VERSION 5.7 ;
  NOWIREEXTENSIONATPIN ON ;
  DIVIDERCHAR "/" ;
  BUSBITCHARS "[]" ;
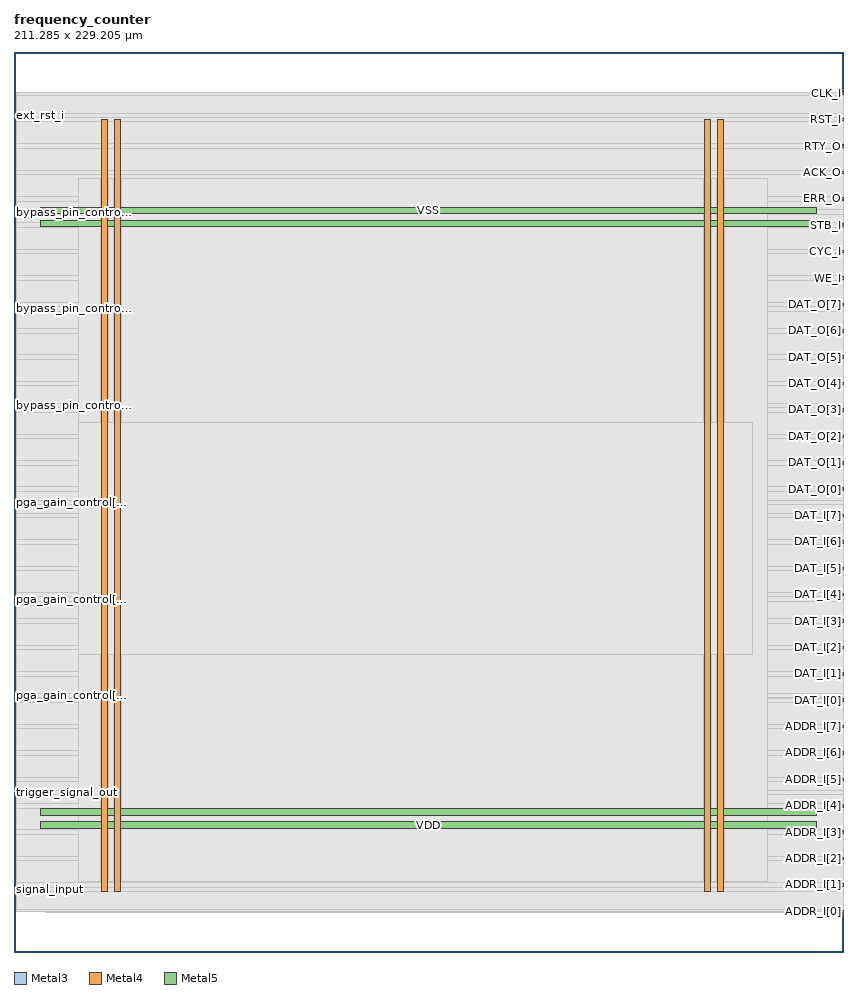
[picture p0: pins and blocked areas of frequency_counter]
MACRO frequency_counter
  CLASS BLOCK ;
  FOREIGN frequency_counter ;
  ORIGIN 0.000 0.000 ;
  SIZE 211.285 BY 229.205 ;
  PIN ACK_O
    DIRECTION OUTPUT ;
    USE SIGNAL ;
    ANTENNADIFFAREA 0.897600 ;
    PORT
      LAYER Metal3 ;
        RECT 210.725 198.240 211.285 198.800 ;
    END
  END ACK_O
  PIN ADDR_I[0]
    DIRECTION INPUT ;
    USE SIGNAL ;
    ANTENNAGATEAREA 0.396000 ;
    PORT
      LAYER Metal3 ;
        RECT 210.725 10.080 211.285 10.640 ;
    END
  END ADDR_I[0]
  PIN ADDR_I[1]
    DIRECTION INPUT ;
    USE SIGNAL ;
    ANTENNAGATEAREA 0.396000 ;
    PORT
      LAYER Metal3 ;
        RECT 210.725 16.800 211.285 17.360 ;
    END
  END ADDR_I[1]
  PIN ADDR_I[2]
    DIRECTION INPUT ;
    USE SIGNAL ;
    ANTENNAGATEAREA 0.396000 ;
    PORT
      LAYER Metal3 ;
        RECT 210.725 23.520 211.285 24.080 ;
    END
  END ADDR_I[2]
  PIN ADDR_I[3]
    DIRECTION INPUT ;
    USE SIGNAL ;
    ANTENNAGATEAREA 0.396000 ;
    PORT
      LAYER Metal3 ;
        RECT 210.725 30.240 211.285 30.800 ;
    END
  END ADDR_I[3]
  PIN ADDR_I[4]
    DIRECTION INPUT ;
    USE SIGNAL ;
    ANTENNAGATEAREA 0.396000 ;
    PORT
      LAYER Metal3 ;
        RECT 210.725 36.960 211.285 37.520 ;
    END
  END ADDR_I[4]
  PIN ADDR_I[5]
    DIRECTION INPUT ;
    USE SIGNAL ;
    ANTENNAGATEAREA 0.396000 ;
    PORT
      LAYER Metal3 ;
        RECT 210.725 43.680 211.285 44.240 ;
    END
  END ADDR_I[5]
  PIN ADDR_I[6]
    DIRECTION INPUT ;
    USE SIGNAL ;
    ANTENNAGATEAREA 0.396000 ;
    PORT
      LAYER Metal3 ;
        RECT 210.725 50.400 211.285 50.960 ;
    END
  END ADDR_I[6]
  PIN ADDR_I[7]
    DIRECTION INPUT ;
    USE SIGNAL ;
    ANTENNAGATEAREA 0.396000 ;
    PORT
      LAYER Metal3 ;
        RECT 210.725 57.120 211.285 57.680 ;
    END
  END ADDR_I[7]
  PIN CLK_I
    DIRECTION INPUT ;
    USE SIGNAL ;
    ANTENNAGATEAREA 4.738000 ;
    PORT
      LAYER Metal3 ;
        RECT 210.725 218.400 211.285 218.960 ;
    END
  END CLK_I
  PIN CYC_I
    DIRECTION INPUT ;
    USE SIGNAL ;
    ANTENNAGATEAREA 0.396000 ;
    PORT
      LAYER Metal3 ;
        RECT 210.725 178.080 211.285 178.640 ;
    END
  END CYC_I
  PIN DAT_I[0]
    DIRECTION INPUT ;
    USE SIGNAL ;
    ANTENNAGATEAREA 0.396000 ;
    PORT
      LAYER Metal3 ;
        RECT 210.725 63.840 211.285 64.400 ;
    END
  END DAT_I[0]
  PIN DAT_I[1]
    DIRECTION INPUT ;
    USE SIGNAL ;
    ANTENNAGATEAREA 0.396000 ;
    PORT
      LAYER Metal3 ;
        RECT 210.725 70.560 211.285 71.120 ;
    END
  END DAT_I[1]
  PIN DAT_I[2]
    DIRECTION INPUT ;
    USE SIGNAL ;
    ANTENNAGATEAREA 0.396000 ;
    PORT
      LAYER Metal3 ;
        RECT 210.725 77.280 211.285 77.840 ;
    END
  END DAT_I[2]
  PIN DAT_I[3]
    DIRECTION INPUT ;
    USE SIGNAL ;
    ANTENNAGATEAREA 0.396000 ;
    PORT
      LAYER Metal3 ;
        RECT 210.725 84.000 211.285 84.560 ;
    END
  END DAT_I[3]
  PIN DAT_I[4]
    DIRECTION INPUT ;
    USE SIGNAL ;
    ANTENNAGATEAREA 0.396000 ;
    PORT
      LAYER Metal3 ;
        RECT 210.725 90.720 211.285 91.280 ;
    END
  END DAT_I[4]
  PIN DAT_I[5]
    DIRECTION INPUT ;
    USE SIGNAL ;
    ANTENNAGATEAREA 0.396000 ;
    PORT
      LAYER Metal3 ;
        RECT 210.725 97.440 211.285 98.000 ;
    END
  END DAT_I[5]
  PIN DAT_I[6]
    DIRECTION INPUT ;
    USE SIGNAL ;
    ANTENNAGATEAREA 0.396000 ;
    PORT
      LAYER Metal3 ;
        RECT 210.725 104.160 211.285 104.720 ;
    END
  END DAT_I[6]
  PIN DAT_I[7]
    DIRECTION INPUT ;
    USE SIGNAL ;
    ANTENNAGATEAREA 0.396000 ;
    PORT
      LAYER Metal3 ;
        RECT 210.725 110.880 211.285 111.440 ;
    END
  END DAT_I[7]
  PIN DAT_O[0]
    DIRECTION OUTPUT ;
    USE SIGNAL ;
    ANTENNADIFFAREA 0.897600 ;
    PORT
      LAYER Metal3 ;
        RECT 210.725 117.600 211.285 118.160 ;
    END
  END DAT_O[0]
  PIN DAT_O[1]
    DIRECTION OUTPUT ;
    USE SIGNAL ;
    ANTENNADIFFAREA 0.897600 ;
    PORT
      LAYER Metal3 ;
        RECT 210.725 124.320 211.285 124.880 ;
    END
  END DAT_O[1]
  PIN DAT_O[2]
    DIRECTION OUTPUT ;
    USE SIGNAL ;
    ANTENNADIFFAREA 0.897600 ;
    PORT
      LAYER Metal3 ;
        RECT 210.725 131.040 211.285 131.600 ;
    END
  END DAT_O[2]
  PIN DAT_O[3]
    DIRECTION OUTPUT ;
    USE SIGNAL ;
    ANTENNADIFFAREA 0.897600 ;
    PORT
      LAYER Metal3 ;
        RECT 210.725 137.760 211.285 138.320 ;
    END
  END DAT_O[3]
  PIN DAT_O[4]
    DIRECTION OUTPUT ;
    USE SIGNAL ;
    ANTENNADIFFAREA 0.897600 ;
    PORT
      LAYER Metal3 ;
        RECT 210.725 144.480 211.285 145.040 ;
    END
  END DAT_O[4]
  PIN DAT_O[5]
    DIRECTION OUTPUT ;
    USE SIGNAL ;
    ANTENNADIFFAREA 0.897600 ;
    PORT
      LAYER Metal3 ;
        RECT 210.725 151.200 211.285 151.760 ;
    END
  END DAT_O[5]
  PIN DAT_O[6]
    DIRECTION OUTPUT ;
    USE SIGNAL ;
    ANTENNADIFFAREA 0.897600 ;
    PORT
      LAYER Metal3 ;
        RECT 210.725 157.920 211.285 158.480 ;
    END
  END DAT_O[6]
  PIN DAT_O[7]
    DIRECTION OUTPUT ;
    USE SIGNAL ;
    ANTENNADIFFAREA 0.897600 ;
    PORT
      LAYER Metal3 ;
        RECT 210.725 164.640 211.285 165.200 ;
    END
  END DAT_O[7]
  PIN ERR_O
    DIRECTION OUTPUT ;
    USE SIGNAL ;
    ANTENNADIFFAREA 0.897600 ;
    PORT
      LAYER Metal3 ;
        RECT 210.725 191.520 211.285 192.080 ;
    END
  END ERR_O
  PIN RST_I
    DIRECTION INPUT ;
    USE SIGNAL ;
    ANTENNAGATEAREA 1.102000 ;
    PORT
      LAYER Metal3 ;
        RECT 210.725 211.680 211.285 212.240 ;
    END
  END RST_I
  PIN RTY_O
    DIRECTION OUTPUT ;
    USE SIGNAL ;
    ANTENNADIFFAREA 0.360800 ;
    PORT
      LAYER Metal3 ;
        RECT 210.725 204.960 211.285 205.520 ;
    END
  END RTY_O
  PIN STB_I
    DIRECTION INPUT ;
    USE SIGNAL ;
    ANTENNAGATEAREA 0.396000 ;
    PORT
      LAYER Metal3 ;
        RECT 210.725 184.800 211.285 185.360 ;
    END
  END STB_I
  PIN VDD
    DIRECTION INOUT ;
    USE POWER ;
    PORT
      LAYER Metal4 ;
        RECT 22.240 15.380 23.840 211.980 ;
    END
    PORT
      LAYER Metal4 ;
        RECT 175.840 15.380 177.440 211.980 ;
    END
    PORT
      LAYER Metal5 ;
        RECT 6.720 31.530 204.400 33.130 ;
    END
    PORT
      LAYER Metal5 ;
        RECT 6.720 184.710 204.400 186.310 ;
    END
  END VDD
  PIN VSS
    DIRECTION INOUT ;
    USE GROUND ;
    PORT
      LAYER Metal4 ;
        RECT 25.540 15.380 27.140 211.980 ;
    END
    PORT
      LAYER Metal4 ;
        RECT 179.140 15.380 180.740 211.980 ;
    END
    PORT
      LAYER Metal5 ;
        RECT 6.720 34.830 204.400 36.430 ;
    END
    PORT
      LAYER Metal5 ;
        RECT 6.720 188.010 204.400 189.610 ;
    END
  END VSS
  PIN WE_I
    DIRECTION INPUT ;
    USE SIGNAL ;
    ANTENNAGATEAREA 0.396000 ;
    PORT
      LAYER Metal3 ;
        RECT 210.725 171.360 211.285 171.920 ;
    END
  END WE_I
  PIN bypass_pin_control[0]
    DIRECTION OUTPUT ;
    USE SIGNAL ;
    ANTENNADIFFAREA 0.897600 ;
    PORT
      LAYER Metal3 ;
        RECT 0.000 138.880 0.560 139.440 ;
    END
  END bypass_pin_control[0]
  PIN bypass_pin_control[1]
    DIRECTION OUTPUT ;
    USE SIGNAL ;
    ANTENNADIFFAREA 0.897600 ;
    PORT
      LAYER Metal3 ;
        RECT 0.000 163.520 0.560 164.080 ;
    END
  END bypass_pin_control[1]
  PIN bypass_pin_control[2]
    DIRECTION OUTPUT ;
    USE SIGNAL ;
    ANTENNADIFFAREA 0.897600 ;
    PORT
      LAYER Metal3 ;
        RECT 0.000 188.160 0.560 188.720 ;
    END
  END bypass_pin_control[2]
  PIN ext_rst_i
    DIRECTION INPUT ;
    USE SIGNAL ;
    PORT
      LAYER Metal3 ;
        RECT 0.000 212.800 0.560 213.360 ;
    END
  END ext_rst_i
  PIN pga_gain_control[0]
    DIRECTION OUTPUT ;
    USE SIGNAL ;
    ANTENNADIFFAREA 0.897600 ;
    PORT
      LAYER Metal3 ;
        RECT 0.000 64.960 0.560 65.520 ;
    END
  END pga_gain_control[0]
  PIN pga_gain_control[1]
    DIRECTION OUTPUT ;
    USE SIGNAL ;
    ANTENNADIFFAREA 0.897600 ;
    PORT
      LAYER Metal3 ;
        RECT 0.000 89.600 0.560 90.160 ;
    END
  END pga_gain_control[1]
  PIN pga_gain_control[2]
    DIRECTION OUTPUT ;
    USE SIGNAL ;
    ANTENNADIFFAREA 0.897600 ;
    PORT
      LAYER Metal3 ;
        RECT 0.000 114.240 0.560 114.800 ;
    END
  END pga_gain_control[2]
  PIN signal_input
    DIRECTION INPUT ;
    USE SIGNAL ;
    ANTENNAGATEAREA 9.476000 ;
    PORT
      LAYER Metal3 ;
        RECT 0.000 15.680 0.560 16.240 ;
    END
  END signal_input
  PIN trigger_signal_out
    DIRECTION OUTPUT ;
    USE SIGNAL ;
    ANTENNADIFFAREA 0.897600 ;
    PORT
      LAYER Metal3 ;
        RECT 0.000 40.320 0.560 40.880 ;
    END
  END trigger_signal_out
  OBS
      LAYER Nwell ;
        RECT 6.290 15.250 204.830 212.110 ;
      LAYER Metal1 ;
        RECT 6.720 15.380 204.400 211.980 ;
      LAYER Metal2 ;
        RECT 7.980 10.170 203.140 218.870 ;
      LAYER Metal3 ;
        RECT 0.560 218.100 210.425 218.820 ;
        RECT 0.560 213.660 211.145 218.100 ;
        RECT 0.860 212.540 211.145 213.660 ;
        RECT 0.860 212.500 210.425 212.540 ;
        RECT 0.560 211.380 210.425 212.500 ;
        RECT 0.560 205.820 211.145 211.380 ;
        RECT 0.560 204.660 210.425 205.820 ;
        RECT 0.560 199.100 211.145 204.660 ;
        RECT 0.560 197.940 210.425 199.100 ;
        RECT 0.560 192.380 211.145 197.940 ;
        RECT 0.560 191.220 210.425 192.380 ;
        RECT 0.560 189.020 211.145 191.220 ;
        RECT 0.860 187.860 211.145 189.020 ;
        RECT 0.560 185.660 211.145 187.860 ;
        RECT 0.560 184.500 210.425 185.660 ;
        RECT 0.560 178.940 211.145 184.500 ;
        RECT 0.560 177.780 210.425 178.940 ;
        RECT 0.560 172.220 211.145 177.780 ;
        RECT 0.560 171.060 210.425 172.220 ;
        RECT 0.560 165.500 211.145 171.060 ;
        RECT 0.560 164.380 210.425 165.500 ;
        RECT 0.860 164.340 210.425 164.380 ;
        RECT 0.860 163.220 211.145 164.340 ;
        RECT 0.560 158.780 211.145 163.220 ;
        RECT 0.560 157.620 210.425 158.780 ;
        RECT 0.560 152.060 211.145 157.620 ;
        RECT 0.560 150.900 210.425 152.060 ;
        RECT 0.560 145.340 211.145 150.900 ;
        RECT 0.560 144.180 210.425 145.340 ;
        RECT 0.560 139.740 211.145 144.180 ;
        RECT 0.860 138.620 211.145 139.740 ;
        RECT 0.860 138.580 210.425 138.620 ;
        RECT 0.560 137.460 210.425 138.580 ;
        RECT 0.560 131.900 211.145 137.460 ;
        RECT 0.560 130.740 210.425 131.900 ;
        RECT 0.560 125.180 211.145 130.740 ;
        RECT 0.560 124.020 210.425 125.180 ;
        RECT 0.560 118.460 211.145 124.020 ;
        RECT 0.560 117.300 210.425 118.460 ;
        RECT 0.560 115.100 211.145 117.300 ;
        RECT 0.860 113.940 211.145 115.100 ;
        RECT 0.560 111.740 211.145 113.940 ;
        RECT 0.560 110.580 210.425 111.740 ;
        RECT 0.560 105.020 211.145 110.580 ;
        RECT 0.560 103.860 210.425 105.020 ;
        RECT 0.560 98.300 211.145 103.860 ;
        RECT 0.560 97.140 210.425 98.300 ;
        RECT 0.560 91.580 211.145 97.140 ;
        RECT 0.560 90.460 210.425 91.580 ;
        RECT 0.860 90.420 210.425 90.460 ;
        RECT 0.860 89.300 211.145 90.420 ;
        RECT 0.560 84.860 211.145 89.300 ;
        RECT 0.560 83.700 210.425 84.860 ;
        RECT 0.560 78.140 211.145 83.700 ;
        RECT 0.560 76.980 210.425 78.140 ;
        RECT 0.560 71.420 211.145 76.980 ;
        RECT 0.560 70.260 210.425 71.420 ;
        RECT 0.560 65.820 211.145 70.260 ;
        RECT 0.860 64.700 211.145 65.820 ;
        RECT 0.860 64.660 210.425 64.700 ;
        RECT 0.560 63.540 210.425 64.660 ;
        RECT 0.560 57.980 211.145 63.540 ;
        RECT 0.560 56.820 210.425 57.980 ;
        RECT 0.560 51.260 211.145 56.820 ;
        RECT 0.560 50.100 210.425 51.260 ;
        RECT 0.560 44.540 211.145 50.100 ;
        RECT 0.560 43.380 210.425 44.540 ;
        RECT 0.560 41.180 211.145 43.380 ;
        RECT 0.860 40.020 211.145 41.180 ;
        RECT 0.560 37.820 211.145 40.020 ;
        RECT 0.560 36.660 210.425 37.820 ;
        RECT 0.560 31.100 211.145 36.660 ;
        RECT 0.560 29.940 210.425 31.100 ;
        RECT 0.560 24.380 211.145 29.940 ;
        RECT 0.560 23.220 210.425 24.380 ;
        RECT 0.560 17.660 211.145 23.220 ;
        RECT 0.560 16.540 210.425 17.660 ;
        RECT 0.860 16.500 210.425 16.540 ;
        RECT 0.860 15.380 211.145 16.500 ;
        RECT 0.560 10.940 211.145 15.380 ;
        RECT 0.560 10.220 210.425 10.940 ;
      LAYER Metal4 ;
        RECT 16.380 18.010 21.940 197.030 ;
        RECT 24.140 18.010 25.240 197.030 ;
        RECT 27.440 18.010 175.540 197.030 ;
        RECT 177.740 18.010 178.840 197.030 ;
        RECT 181.040 18.010 191.940 197.030 ;
      LAYER Metal5 ;
        RECT 16.300 75.830 188.100 134.770 ;
  END
END frequency_counter
END LIBRARY

